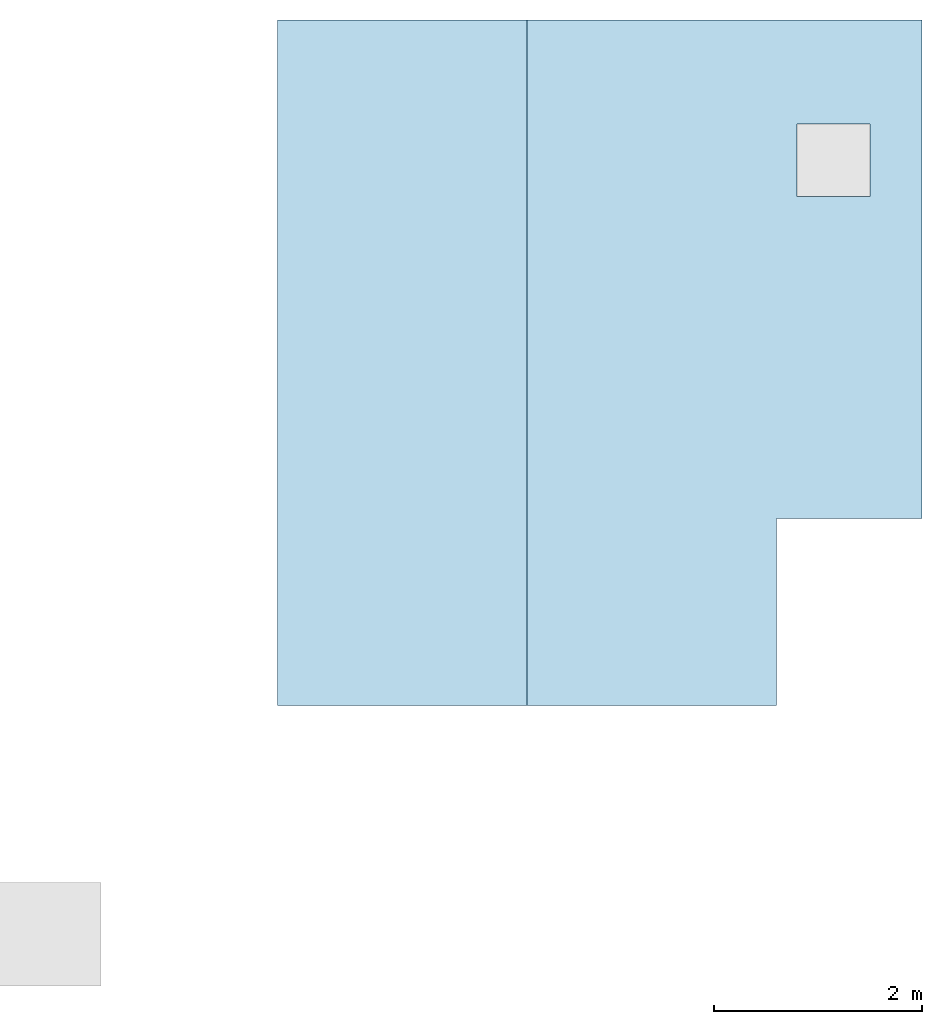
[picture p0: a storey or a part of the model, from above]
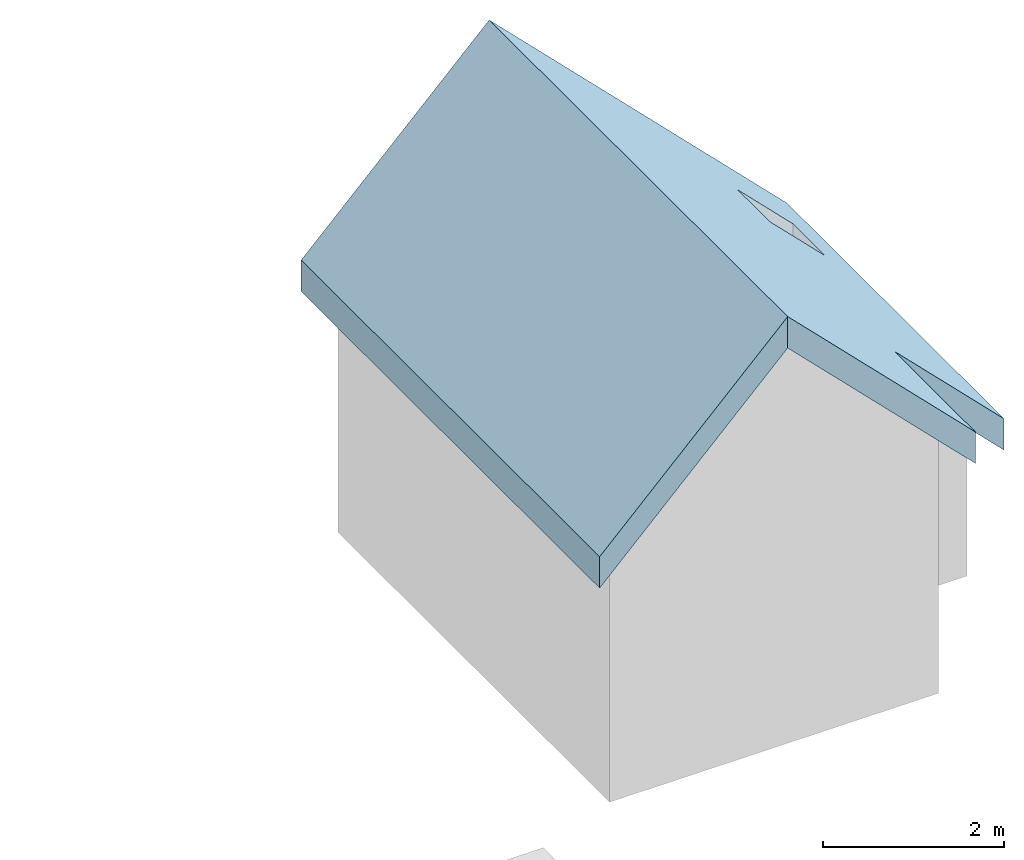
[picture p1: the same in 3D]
Properties of the parts of a building model (IFC2X3)

# File
Description: ViewDefinition [CoordinationView_V2.0]
File name: Building-Architecture.ifc
Time: 2026-06-23T11:53:12
Written by: Sketchup-IFC-manager 5.6.0 / SketchUp 2026 (26.2.242)
Made in: BIM_Tools - Sketchup_IFC_manager - 5.6.0

# IfcProject, ifc silly sample scene - project
Description: Demystifying IFC with a playful scene using diverse building elements and compositions.

# IfcSite, environment - site
Description: A sample scene environment, showcasing the surrounding landscape.; RefElevation: 0 mm

# IfcBuilding: house, Single-family house
Description: The main building structure, providing shelter and space.; LongName: house - building; Classification: E-AAA Single-family house (CCI Construction)

# IfcBuildingStorey: buildingstorey, 00 groundfloor
In: Single-family house
Description: The ground floor, forming the base level of the building.; Elevation: 0 mm

# IfcSpace: house - entry hall, entry hall
In: 00 groundfloor
Type - Description: A welcoming entry hall, the first impression of the home.; ElementType: hallway
ElevationWithFlooring: 0 mm; Group: house - living space

# IfcSpace: house - living room, living room
In: 00 groundfloor
Type - Description: A cozy space, perfect for relaxation and family gatherings.; ElementType: living area
ElevationWithFlooring: 0 mm; Group: house - living space

# IfcBuildingElementProxy: geo-reference
In: environment - site
Type - Description: The reference point for transforming the local engineering coordinate system into the coordinate reference system of the underlying map.; ElementType: origin
Material: virtual_black

# IfcBuildingElementProxy: house - chimney
In: 00 groundfloor
Type - Description: A chimney, standing tall and proud, guiding smoke away from the home.; ElementType: flue
Material: stone_sand-lime

# IfcBuildingElementProxy: house - gross volume
In: environment - site
Type - ElementType: gross volume
Material: virtual_spatial-zone

# IfcBuildingElementProxy: origin
In: environment - site
Type - Description: The local position for coordination of aspect models.; ElementType: origin
Material: virtual_white

# IfcBuildingElementProxy: sand bedding
In: environment - site
Type - Description: A layer of ground floor sand bedding, providing a stable base.; ElementType: subgrade
Material: bulk-material_sand-coarse_generic

# IfcFurnishingElement: house - kitchen, kitchen
In: living room
Type - Description: The heart of the home, where meals are prepared and shared.; ElementType: kitchen
Material: wood_mdf_plate

# IfcRoof: gable_roof, house - roof
In: environment - site
Description: A sturdy roof, sheltering the house from the elements.; ShapeType: GABLE_ROOF

# IfcSlab: house - groundfloor, floor
In: 00 groundfloor
Type - Description: A solid, site-cast concrete floor, providing a strong foundation.; ElementType: slab on grade; PredefinedType: FLOOR
Type - Pset_SlabCommon - FireRating: REI60; SurfaceSpreadOfFlame: A2 s1 d0
Material: concrete_reinforced_in-situ
Pset_SlabCommon - IsExternal: yes; LoadBearing: no; FireRating: REI30; AcousticRating: 29dB Rw
Qto_SlabBaseQuantities - NetVolume: 6.4375 m3; Depth: 250 mm; NetArea: 25.75 m2

# IfcSlab: house - roof - slab left
In: environment - site
Type - Description: A roof slab that's got it all covered; ElementType: roof; PredefinedType: ROOF
Material: composite_element_roof
Qto_SlabBaseQuantities - NetVolume: 6.72034 m3; Depth: 300 mm; NetArea: 22.4011 m2

# IfcSlab: house - roof - slab right
In: environment - site
Type - Description: A roof slab that's got it all covered; ElementType: roof; PredefinedType: ROOF
Material: composite_element_roof
Qto_SlabBaseQuantities - NetVolume: 9.36351 m3; Depth: 300 mm; NetArea: 31.2117 m2

# IfcWall: house - outer wall - house left
In: 00 groundfloor
Type - Description: A solid outer wall, forming the left side of the house.; ElementType: solidwall
Material: stone_sand-lime
Qto_WallBaseQuantities - NetVolume: 4.23088 m3; Width: 200 mm; Length: 6000 mm; NetSideArea: 21.1544 m2

# IfcWall: house - outer wall - house right back
In: 00 groundfloor
Type - Description: A solid outer wall, forming the right back side of the house.; ElementType: solidwall
Material: stone_sand-lime
Qto_WallBaseQuantities - NetVolume: 1.78562 m3; Width: 200 mm; Length: 4200 mm; NetSideArea: 8.92809 m2

# IfcWall: house - outer wall - house right front
In: 00 groundfloor
Type - Description: A solid outer wall, forming the right front side of the house.; ElementType: solidwall
Material: stone_sand-lime
Qto_WallBaseQuantities - NetVolume: 1.26926 m3; Width: 200 mm; Length: 1800 mm; NetSideArea: 6.34632 m2

# IfcWall: plumbing wall
In: 00 groundfloor
Type - Description: A wall designed to house and protect plumbing systems, keeping the pipes snug and secure.; ElementType: plumbingwall
Material: gypsum_fiber-board_panel
Qto_WallBaseQuantities - NetVolume: 0.164702 m3; Width: 24 mm; Length: 3800 mm; NetSideArea: 6.86258 m2

# IfcZone: living space, house - living space
Description: A cozy living space, perfect for relaxation and gatherings.
